VERSION 5.8 ;
NAMESCASESENSITIVE ON ;
BUSBITCHARS "[]" ;
DIVIDERCHAR "/" ;

PROPERTYDEFINITIONS
END PROPERTYDEFINITIONS

UNITS
    DATABASE MICRONS 2000 ;
END UNITS

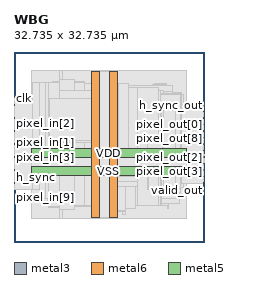
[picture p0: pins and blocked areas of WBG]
MACRO WBG
    CLASS BLOCK ;
    SIZE 32.735 BY 32.735 ;
    PIN clk
        DIRECTION INPUT ; 
        USE CLOCK ; 
        PORT
            LAYER metal3 ;
              RECT  0 24.675 0.07 24.745 ;
        END
    END clk
    PIN h_sync
        DIRECTION INPUT ; 
        USE SIGNAL ; 
        PORT
            LAYER metal3 ;
              RECT  0 12.355 0.07 12.425 ;
        END
    END h_sync
    PIN h_sync_out
        DIRECTION OUTPUT ; 
        USE SIGNAL ; 
        PORT
            LAYER metal3 ;
              RECT  32.665 23.555 32.735 23.625 ;
        END
    END h_sync_out
    PIN pixel_in[0]
        DIRECTION INPUT ; 
        USE SIGNAL ; 
        PORT
            LAYER metal3 ;
              RECT  0 10.115 0.07 10.185 ;
        END
    END pixel_in[0]
    PIN pixel_in[1]
        DIRECTION INPUT ; 
        USE SIGNAL ; 
        PORT
            LAYER metal3 ;
              RECT  0 15.715 0.07 15.785 ;
        END
    END pixel_in[1]
    PIN pixel_in[2]
        DIRECTION INPUT ; 
        USE SIGNAL ; 
        PORT
            LAYER metal3 ;
              RECT  0 19.075 0.07 19.145 ;
        END
    END pixel_in[2]
    PIN pixel_in[3]
        DIRECTION INPUT ; 
        USE SIGNAL ; 
        PORT
            LAYER metal3 ;
              RECT  0 14.595 0.07 14.665 ;
        END
    END pixel_in[3]
    PIN pixel_in[4]
        DIRECTION INPUT ; 
        USE SIGNAL ; 
        PORT
            LAYER metal3 ;
              RECT  0 11.235 0.07 11.305 ;
        END
    END pixel_in[4]
    PIN pixel_in[5]
        DIRECTION INPUT ; 
        USE SIGNAL ; 
        PORT
            LAYER metal3 ;
              RECT  0 13.475 0.07 13.545 ;
        END
    END pixel_in[5]
    PIN pixel_in[6]
        DIRECTION INPUT ; 
        USE SIGNAL ; 
        PORT
            LAYER metal3 ;
              RECT  0 17.955 0.07 18.025 ;
        END
    END pixel_in[6]
    PIN pixel_in[7]
        DIRECTION INPUT ; 
        USE SIGNAL ; 
        PORT
            LAYER metal3 ;
              RECT  0 20.195 0.07 20.265 ;
        END
    END pixel_in[7]
    PIN pixel_in[8]
        DIRECTION INPUT ; 
        USE SIGNAL ; 
        PORT
            LAYER metal3 ;
              RECT  0 16.835 0.07 16.905 ;
        END
    END pixel_in[8]
    PIN pixel_in[9]
        DIRECTION INPUT ; 
        USE SIGNAL ; 
        PORT
            LAYER metal3 ;
              RECT  0 8.995 0.07 9.065 ;
        END
    END pixel_in[9]
    PIN pixel_out[0]
        DIRECTION OUTPUT ; 
        USE SIGNAL ; 
        PORT
            LAYER metal3 ;
              RECT  32.665 20.195 32.735 20.265 ;
        END
    END pixel_out[0]
    PIN pixel_out[1]
        DIRECTION OUTPUT ; 
        USE SIGNAL ; 
        PORT
            LAYER metal3 ;
              RECT  32.665 17.955 32.735 18.025 ;
        END
    END pixel_out[1]
    PIN pixel_out[2]
        DIRECTION OUTPUT ; 
        USE SIGNAL ; 
        PORT
            LAYER metal3 ;
              RECT  32.665 14.595 32.735 14.665 ;
        END
    END pixel_out[2]
    PIN pixel_out[3]
        DIRECTION OUTPUT ; 
        USE SIGNAL ; 
        PORT
            LAYER metal3 ;
              RECT  32.665 13.475 32.735 13.545 ;
        END
    END pixel_out[3]
    PIN pixel_out[4]
        DIRECTION OUTPUT ; 
        USE SIGNAL ; 
        PORT
            LAYER metal3 ;
              RECT  32.665 21.315 32.735 21.385 ;
        END
    END pixel_out[4]
    PIN pixel_out[5]
        DIRECTION OUTPUT ; 
        USE SIGNAL ; 
        PORT
            LAYER metal3 ;
              RECT  32.665 22.435 32.735 22.505 ;
        END
    END pixel_out[5]
    PIN pixel_out[6]
        DIRECTION OUTPUT ; 
        USE SIGNAL ; 
        PORT
            LAYER metal3 ;
              RECT  32.665 12.355 32.735 12.425 ;
        END
    END pixel_out[6]
    PIN pixel_out[7]
        DIRECTION OUTPUT ; 
        USE SIGNAL ; 
        PORT
            LAYER metal3 ;
              RECT  32.665 11.235 32.735 11.305 ;
        END
    END pixel_out[7]
    PIN pixel_out[8]
        DIRECTION OUTPUT ; 
        USE SIGNAL ; 
        PORT
            LAYER metal3 ;
              RECT  32.665 19.075 32.735 19.145 ;
        END
    END pixel_out[8]
    PIN pixel_out[9]
        DIRECTION OUTPUT ; 
        USE SIGNAL ; 
        PORT
            LAYER metal3 ;
              RECT  32.665 16.835 32.735 16.905 ;
        END
    END pixel_out[9]
    PIN resetn
        DIRECTION INPUT ; 
        USE SIGNAL ; 
        PORT
            LAYER metal3 ;
              RECT  0 22.435 0.07 22.505 ;
        END
    END resetn
    PIN v_sync
        DIRECTION INPUT ; 
        USE SIGNAL ; 
        PORT
            LAYER metal3 ;
              RECT  0 21.315 0.07 21.385 ;
        END
    END v_sync
    PIN v_sync_out
        DIRECTION OUTPUT ; 
        USE SIGNAL ; 
        PORT
            LAYER metal3 ;
              RECT  32.665 15.715 32.735 15.785 ;
        END
    END v_sync_out
    PIN valid_in
        DIRECTION INPUT ; 
        USE SIGNAL ; 
        PORT
            LAYER metal3 ;
              RECT  0 23.555 0.07 23.625 ;
        END
    END valid_in
    PIN valid_out
        DIRECTION OUTPUT ; 
        USE SIGNAL ; 
        PORT
            LAYER metal3 ;
              RECT  32.665 10.115 32.735 10.185 ;
        END
    END valid_out
    PIN VSS
        DIRECTION INOUT ; 
        USE GROUND ; 
        PORT
            LAYER metal6 ;
              RECT  13.29 4.16 14.79 29.44 ;
            LAYER metal5 ;
              RECT  3.04 11.45 29.64 12.95 ;
        END
    END VSS
    PIN VDD
        DIRECTION INOUT ; 
        USE POWER ; 
        PORT
            LAYER metal6 ;
              RECT  16.39 4.16 17.89 29.44 ;
            LAYER metal5 ;
              RECT  3.04 14.55 29.64 16.05 ;
        END
    END VDD
    OBS
      LAYER metal1 ;
        RECT  3.04 4.115 29.64 29.485 ;
      LAYER metal2 ;
        RECT  18.68 4.76 19.13 5.32 ;
        RECT  7.81 4.13 8.27 5.53 ;
        RECT  15.45 5.32 19.13 5.74 ;
        RECT  7.81 5.53 10.37 6.02 ;
        RECT  5.95 6.02 10.37 6.16 ;
        RECT  15.45 5.74 20.84 6.16 ;
        RECT  5.95 6.16 20.84 6.3 ;
        RECT  26.47 5.74 26.54 6.3 ;
        RECT  5.76 6.3 26.54 6.58 ;
        RECT  5.76 6.58 28.44 7.42 ;
        RECT  4.43 7.42 28.44 8.575 ;
        RECT  4.43 8.575 28.63 9.38 ;
        RECT  4.43 9.38 29.2 10.36 ;
        RECT  4.24 10.36 29.2 11.2 ;
        RECT  4.05 11.2 29.2 12.32 ;
        RECT  3.29 12.32 29.2 25.48 ;
        RECT  3.29 25.48 28.82 25.76 ;
        RECT  3.29 25.76 27.3 26.88 ;
        RECT  23.81 26.88 27.3 27.02 ;
        RECT  23.81 27.02 26.35 27.16 ;
        RECT  24.19 27.16 26.35 27.265 ;
        RECT  3.29 26.88 19.7 27.3 ;
        RECT  24.19 27.265 26.16 27.3 ;
        RECT  3.29 27.3 12.1 27.44 ;
        RECT  6.71 27.44 12.1 27.58 ;
        RECT  7.81 27.58 10.37 28.07 ;
        RECT  7.81 28.07 8.27 29.47 ;
      LAYER metal3 ;
        RECT  0 14.735 0.035 16.765 ;
        RECT  0.035 8.995 3.255 24.745 ;
        RECT  3.255 8.995 4.395 27.405 ;
        RECT  4.395 7.455 5.38 27.405 ;
        RECT  5.38 7.455 5.915 27.545 ;
        RECT  5.915 6.055 7.81 27.545 ;
        RECT  7.81 4.13 8.27 29.47 ;
        RECT  8.27 5.53 10.37 28.07 ;
        RECT  10.37 6.335 12.135 27.545 ;
        RECT  12.135 6.335 13.705 27.265 ;
        RECT  13.705 6.195 14.225 27.265 ;
        RECT  14.225 6.195 15.415 9.485 ;
        RECT  14.225 12.355 18.025 27.265 ;
        RECT  15.415 5.355 19.165 9.485 ;
        RECT  18.025 12.915 19.735 27.265 ;
        RECT  19.165 5.775 20.875 9.485 ;
        RECT  20.875 6.335 21.305 9.485 ;
        RECT  19.735 12.915 21.305 26.565 ;
        RECT  21.305 6.335 24.865 26.565 ;
        RECT  24.865 6.335 25.245 26.145 ;
        RECT  25.245 6.335 25.435 22.645 ;
        RECT  25.435 8.715 25.815 22.645 ;
        RECT  25.245 25.655 25.815 26.145 ;
        RECT  25.815 25.655 26.195 26.005 ;
        RECT  26.195 25.655 27.335 25.865 ;
        RECT  25.815 9.135 27.905 22.645 ;
        RECT  27.905 9.275 28.665 22.645 ;
        RECT  28.665 10.115 28.715 22.645 ;
        RECT  27.335 25.655 28.715 25.725 ;
        RECT  28.715 10.115 28.855 25.725 ;
        RECT  28.855 10.115 32.7 23.625 ;
        RECT  32.7 13.615 32.735 15.085 ;
      LAYER metal4 ;
        RECT  7.79 4.13 8.29 5.53 ;
        RECT  22.985 9.1 23.125 15.96 ;
        RECT  7.79 5.53 10.39 17.22 ;
        RECT  22.985 15.96 25.645 17.36 ;
        RECT  7.79 17.22 16.125 17.5 ;
        RECT  6.185 17.5 16.125 24.78 ;
        RECT  7.79 24.78 16.125 26.04 ;
        RECT  7.79 26.04 10.39 28.07 ;
        RECT  7.79 28.07 8.29 29.47 ;
      LAYER metal5 ;
        RECT  3.04 11.45 29.64 16.05 ;
      LAYER metal6 ;
        RECT  13.29 4.16 17.89 29.44 ;
    END
END WBG
END LIBRARY
